VERSION 5.7 ;
BUSBITCHARS "[]" ;
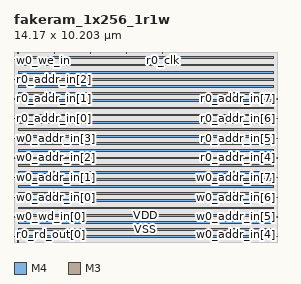
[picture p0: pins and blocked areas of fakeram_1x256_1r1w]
MACRO fakeram_1x256_1r1w
  FOREIGN fakeram_1x256_1r1w 0 0 ;
  SYMMETRY X Y R90 ;
  SIZE 14.170 BY 10.203 ;
  CLASS BLOCK ;
  PIN w0_wmask_in[0]
    DIRECTION INPUT ;
    USE SIGNAL ;
    SHAPE ABUTMENT ;
    PORT
      LAYER M4 ;
      RECT 0.000 0.276 0.072 0.300 ;
    END
  END w0_wmask_in[0]
  PIN w0_wd_in[0]
    DIRECTION INPUT ;
    USE SIGNAL ;
    SHAPE ABUTMENT ;
    PORT
      LAYER M4 ;
      RECT 0.000 1.332 0.072 1.356 ;
    END
  END w0_wd_in[0]
  PIN r0_rd_out[0]
    DIRECTION OUTPUT ;
    USE SIGNAL ;
    SHAPE ABUTMENT ;
    PORT
      LAYER M3 ;
      RECT 0.207 0.000 0.225 0.054 ;
    END
  END r0_rd_out[0]
  PIN w0_addr_in[0]
    DIRECTION INPUT ;
    USE SIGNAL ;
    SHAPE ABUTMENT ;
    PORT
      LAYER M4 ;
      RECT 0.000 2.388 0.072 2.412 ;
    END
  END w0_addr_in[0]
  PIN w0_addr_in[1]
    DIRECTION INPUT ;
    USE SIGNAL ;
    SHAPE ABUTMENT ;
    PORT
      LAYER M4 ;
      RECT 0.000 3.444 0.072 3.468 ;
    END
  END w0_addr_in[1]
  PIN w0_addr_in[2]
    DIRECTION INPUT ;
    USE SIGNAL ;
    SHAPE ABUTMENT ;
    PORT
      LAYER M4 ;
      RECT 0.000 4.500 0.072 4.524 ;
    END
  END w0_addr_in[2]
  PIN w0_addr_in[3]
    DIRECTION INPUT ;
    USE SIGNAL ;
    SHAPE ABUTMENT ;
    PORT
      LAYER M4 ;
      RECT 0.000 5.556 0.072 5.580 ;
    END
  END w0_addr_in[3]
  PIN w0_addr_in[4]
    DIRECTION INPUT ;
    USE SIGNAL ;
    SHAPE ABUTMENT ;
    PORT
      LAYER M4 ;
      RECT 14.098 0.276 14.170 0.300 ;
    END
  END w0_addr_in[4]
  PIN w0_addr_in[5]
    DIRECTION INPUT ;
    USE SIGNAL ;
    SHAPE ABUTMENT ;
    PORT
      LAYER M4 ;
      RECT 14.098 1.332 14.170 1.356 ;
    END
  END w0_addr_in[5]
  PIN w0_addr_in[6]
    DIRECTION INPUT ;
    USE SIGNAL ;
    SHAPE ABUTMENT ;
    PORT
      LAYER M4 ;
      RECT 14.098 2.388 14.170 2.412 ;
    END
  END w0_addr_in[6]
  PIN w0_addr_in[7]
    DIRECTION INPUT ;
    USE SIGNAL ;
    SHAPE ABUTMENT ;
    PORT
      LAYER M4 ;
      RECT 14.098 3.444 14.170 3.468 ;
    END
  END w0_addr_in[7]
  PIN r0_addr_in[0]
    DIRECTION INPUT ;
    USE SIGNAL ;
    SHAPE ABUTMENT ;
    PORT
      LAYER M4 ;
      RECT 0.000 6.612 0.072 6.636 ;
    END
  END r0_addr_in[0]
  PIN r0_addr_in[1]
    DIRECTION INPUT ;
    USE SIGNAL ;
    SHAPE ABUTMENT ;
    PORT
      LAYER M4 ;
      RECT 0.000 7.668 0.072 7.692 ;
    END
  END r0_addr_in[1]
  PIN r0_addr_in[2]
    DIRECTION INPUT ;
    USE SIGNAL ;
    SHAPE ABUTMENT ;
    PORT
      LAYER M4 ;
      RECT 0.000 8.724 0.072 8.748 ;
    END
  END r0_addr_in[2]
  PIN r0_addr_in[3]
    DIRECTION INPUT ;
    USE SIGNAL ;
    SHAPE ABUTMENT ;
    PORT
      LAYER M4 ;
      RECT 0.000 9.780 0.072 9.804 ;
    END
  END r0_addr_in[3]
  PIN r0_addr_in[4]
    DIRECTION INPUT ;
    USE SIGNAL ;
    SHAPE ABUTMENT ;
    PORT
      LAYER M4 ;
      RECT 14.098 4.500 14.170 4.524 ;
    END
  END r0_addr_in[4]
  PIN r0_addr_in[5]
    DIRECTION INPUT ;
    USE SIGNAL ;
    SHAPE ABUTMENT ;
    PORT
      LAYER M4 ;
      RECT 14.098 5.556 14.170 5.580 ;
    END
  END r0_addr_in[5]
  PIN r0_addr_in[6]
    DIRECTION INPUT ;
    USE SIGNAL ;
    SHAPE ABUTMENT ;
    PORT
      LAYER M4 ;
      RECT 14.098 6.612 14.170 6.636 ;
    END
  END r0_addr_in[6]
  PIN r0_addr_in[7]
    DIRECTION INPUT ;
    USE SIGNAL ;
    SHAPE ABUTMENT ;
    PORT
      LAYER M4 ;
      RECT 14.098 7.668 14.170 7.692 ;
    END
  END r0_addr_in[7]
  PIN w0_we_in
    DIRECTION INPUT ;
    USE SIGNAL ;
    SHAPE ABUTMENT ;
    PORT
      LAYER M3 ;
      RECT 0.207 10.149 0.225 10.203 ;
    END
  END w0_we_in
  PIN w0_ce_in
    DIRECTION INPUT ;
    USE SIGNAL ;
    SHAPE ABUTMENT ;
    PORT
      LAYER M3 ;
      RECT 2.151 10.149 2.169 10.203 ;
    END
  END w0_ce_in
  PIN w0_clk
    DIRECTION INPUT ;
    USE SIGNAL ;
    SHAPE ABUTMENT ;
    PORT
      LAYER M3 ;
      RECT 4.095 10.149 4.113 10.203 ;
    END
  END w0_clk
  PIN r0_ce_in
    DIRECTION INPUT ;
    USE SIGNAL ;
    SHAPE ABUTMENT ;
    PORT
      LAYER M3 ;
      RECT 6.039 10.149 6.057 10.203 ;
    END
  END r0_ce_in
  PIN r0_clk
    DIRECTION INPUT ;
    USE SIGNAL ;
    SHAPE ABUTMENT ;
    PORT
      LAYER M3 ;
      RECT 7.983 10.149 8.001 10.203 ;
    END
  END r0_clk
  PIN VSS
    DIRECTION INOUT ;
    USE GROUND ;
    PORT
      LAYER M4 ;
      RECT 0.216 0.240 13.954 0.336 ;
      RECT 0.216 1.008 13.954 1.104 ;
      RECT 0.216 1.776 13.954 1.872 ;
      RECT 0.216 2.544 13.954 2.640 ;
      RECT 0.216 3.312 13.954 3.408 ;
      RECT 0.216 4.080 13.954 4.176 ;
      RECT 0.216 4.848 13.954 4.944 ;
      RECT 0.216 5.616 13.954 5.712 ;
      RECT 0.216 6.384 13.954 6.480 ;
      RECT 0.216 7.152 13.954 7.248 ;
      RECT 0.216 7.920 13.954 8.016 ;
      RECT 0.216 8.688 13.954 8.784 ;
      RECT 0.216 9.456 13.954 9.552 ;
    END
  END VSS
  PIN VDD
    DIRECTION INOUT ;
    USE POWER ;
    PORT
      LAYER M4 ;
      RECT 0.216 0.624 13.954 0.720 ;
      RECT 0.216 1.392 13.954 1.488 ;
      RECT 0.216 2.160 13.954 2.256 ;
      RECT 0.216 2.928 13.954 3.024 ;
      RECT 0.216 3.696 13.954 3.792 ;
      RECT 0.216 4.464 13.954 4.560 ;
      RECT 0.216 5.232 13.954 5.328 ;
      RECT 0.216 6.000 13.954 6.096 ;
      RECT 0.216 6.768 13.954 6.864 ;
      RECT 0.216 7.536 13.954 7.632 ;
      RECT 0.216 8.304 13.954 8.400 ;
      RECT 0.216 9.072 13.954 9.168 ;
      RECT 0.216 9.840 13.954 9.936 ;
    END
  END VDD
  OBS
    LAYER M1 ;
    RECT 0 0 14.170 10.203 ;
    LAYER M2 ;
    RECT 0 0 14.170 10.203 ;
    LAYER M3 ;
    RECT 0 0 14.170 10.203 ;
    LAYER M4 ;
    RECT 0 0 14.170 10.203 ;
  END
END fakeram_1x256_1r1w

END LIBRARY
